VERSION 5.7 ;
BUSBITCHARS "[]" ;
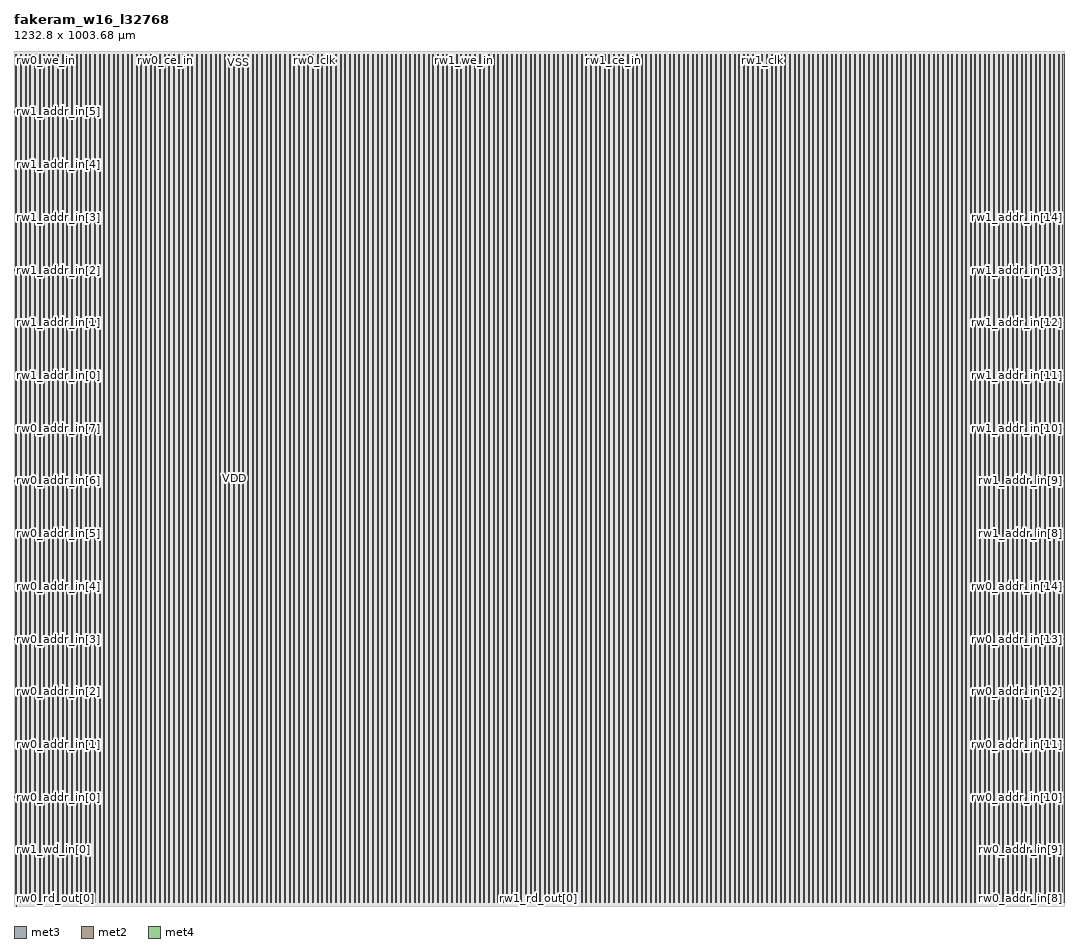
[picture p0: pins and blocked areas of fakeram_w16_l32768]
MACRO fakeram_w16_l32768
  FOREIGN fakeram_w16_l32768 0 0 ;
  SYMMETRY X Y R90 ;
  SIZE 1232.800 BY 1003.680 ;
  CLASS BLOCK ;
  PIN rw0_wd_in[0]
    DIRECTION INPUT ;
    USE SIGNAL ;
    SHAPE ABUTMENT ;
    PORT
      LAYER met3 ;
      RECT 0.000 3.930 0.900 4.230 ;
    END
  END rw0_wd_in[0]
  PIN rw1_wd_in[0]
    DIRECTION INPUT ;
    USE SIGNAL ;
    SHAPE ABUTMENT ;
    PORT
      LAYER met3 ;
      RECT 0.000 65.810 0.900 66.110 ;
    END
  END rw1_wd_in[0]
  PIN rw0_rd_out[0]
    DIRECTION OUTPUT ;
    USE SIGNAL ;
    SHAPE ABUTMENT ;
    PORT
      LAYER met2 ;
      RECT 2.690 0.000 2.830 0.420 ;
    END
  END rw0_rd_out[0]
  PIN rw1_rd_out[0]
    DIRECTION OUTPUT ;
    USE SIGNAL ;
    SHAPE ABUTMENT ;
    PORT
      LAYER met2 ;
      RECT 615.870 0.000 616.010 0.420 ;
    END
  END rw1_rd_out[0]
  PIN rw0_addr_in[0]
    DIRECTION INPUT ;
    USE SIGNAL ;
    SHAPE ABUTMENT ;
    PORT
      LAYER met3 ;
      RECT 0.000 127.690 0.900 127.990 ;
    END
  END rw0_addr_in[0]
  PIN rw0_addr_in[1]
    DIRECTION INPUT ;
    USE SIGNAL ;
    SHAPE ABUTMENT ;
    PORT
      LAYER met3 ;
      RECT 0.000 189.570 0.900 189.870 ;
    END
  END rw0_addr_in[1]
  PIN rw0_addr_in[2]
    DIRECTION INPUT ;
    USE SIGNAL ;
    SHAPE ABUTMENT ;
    PORT
      LAYER met3 ;
      RECT 0.000 251.450 0.900 251.750 ;
    END
  END rw0_addr_in[2]
  PIN rw0_addr_in[3]
    DIRECTION INPUT ;
    USE SIGNAL ;
    SHAPE ABUTMENT ;
    PORT
      LAYER met3 ;
      RECT 0.000 313.330 0.900 313.630 ;
    END
  END rw0_addr_in[3]
  PIN rw0_addr_in[4]
    DIRECTION INPUT ;
    USE SIGNAL ;
    SHAPE ABUTMENT ;
    PORT
      LAYER met3 ;
      RECT 0.000 375.210 0.900 375.510 ;
    END
  END rw0_addr_in[4]
  PIN rw0_addr_in[5]
    DIRECTION INPUT ;
    USE SIGNAL ;
    SHAPE ABUTMENT ;
    PORT
      LAYER met3 ;
      RECT 0.000 437.090 0.900 437.390 ;
    END
  END rw0_addr_in[5]
  PIN rw0_addr_in[6]
    DIRECTION INPUT ;
    USE SIGNAL ;
    SHAPE ABUTMENT ;
    PORT
      LAYER met3 ;
      RECT 0.000 498.970 0.900 499.270 ;
    END
  END rw0_addr_in[6]
  PIN rw0_addr_in[7]
    DIRECTION INPUT ;
    USE SIGNAL ;
    SHAPE ABUTMENT ;
    PORT
      LAYER met3 ;
      RECT 0.000 560.850 0.900 561.150 ;
    END
  END rw0_addr_in[7]
  PIN rw0_addr_in[8]
    DIRECTION INPUT ;
    USE SIGNAL ;
    SHAPE ABUTMENT ;
    PORT
      LAYER met3 ;
      RECT 1231.900 3.930 1232.800 4.230 ;
    END
  END rw0_addr_in[8]
  PIN rw0_addr_in[9]
    DIRECTION INPUT ;
    USE SIGNAL ;
    SHAPE ABUTMENT ;
    PORT
      LAYER met3 ;
      RECT 1231.900 65.810 1232.800 66.110 ;
    END
  END rw0_addr_in[9]
  PIN rw0_addr_in[10]
    DIRECTION INPUT ;
    USE SIGNAL ;
    SHAPE ABUTMENT ;
    PORT
      LAYER met3 ;
      RECT 1231.900 127.690 1232.800 127.990 ;
    END
  END rw0_addr_in[10]
  PIN rw0_addr_in[11]
    DIRECTION INPUT ;
    USE SIGNAL ;
    SHAPE ABUTMENT ;
    PORT
      LAYER met3 ;
      RECT 1231.900 189.570 1232.800 189.870 ;
    END
  END rw0_addr_in[11]
  PIN rw0_addr_in[12]
    DIRECTION INPUT ;
    USE SIGNAL ;
    SHAPE ABUTMENT ;
    PORT
      LAYER met3 ;
      RECT 1231.900 251.450 1232.800 251.750 ;
    END
  END rw0_addr_in[12]
  PIN rw0_addr_in[13]
    DIRECTION INPUT ;
    USE SIGNAL ;
    SHAPE ABUTMENT ;
    PORT
      LAYER met3 ;
      RECT 1231.900 313.330 1232.800 313.630 ;
    END
  END rw0_addr_in[13]
  PIN rw0_addr_in[14]
    DIRECTION INPUT ;
    USE SIGNAL ;
    SHAPE ABUTMENT ;
    PORT
      LAYER met3 ;
      RECT 1231.900 375.210 1232.800 375.510 ;
    END
  END rw0_addr_in[14]
  PIN rw1_addr_in[0]
    DIRECTION INPUT ;
    USE SIGNAL ;
    SHAPE ABUTMENT ;
    PORT
      LAYER met3 ;
      RECT 0.000 622.730 0.900 623.030 ;
    END
  END rw1_addr_in[0]
  PIN rw1_addr_in[1]
    DIRECTION INPUT ;
    USE SIGNAL ;
    SHAPE ABUTMENT ;
    PORT
      LAYER met3 ;
      RECT 0.000 684.610 0.900 684.910 ;
    END
  END rw1_addr_in[1]
  PIN rw1_addr_in[2]
    DIRECTION INPUT ;
    USE SIGNAL ;
    SHAPE ABUTMENT ;
    PORT
      LAYER met3 ;
      RECT 0.000 746.490 0.900 746.790 ;
    END
  END rw1_addr_in[2]
  PIN rw1_addr_in[3]
    DIRECTION INPUT ;
    USE SIGNAL ;
    SHAPE ABUTMENT ;
    PORT
      LAYER met3 ;
      RECT 0.000 808.370 0.900 808.670 ;
    END
  END rw1_addr_in[3]
  PIN rw1_addr_in[4]
    DIRECTION INPUT ;
    USE SIGNAL ;
    SHAPE ABUTMENT ;
    PORT
      LAYER met3 ;
      RECT 0.000 870.250 0.900 870.550 ;
    END
  END rw1_addr_in[4]
  PIN rw1_addr_in[5]
    DIRECTION INPUT ;
    USE SIGNAL ;
    SHAPE ABUTMENT ;
    PORT
      LAYER met3 ;
      RECT 0.000 932.130 0.900 932.430 ;
    END
  END rw1_addr_in[5]
  PIN rw1_addr_in[6]
    DIRECTION INPUT ;
    USE SIGNAL ;
    SHAPE ABUTMENT ;
    PORT
      LAYER met3 ;
      RECT 0.000 994.010 0.900 994.310 ;
    END
  END rw1_addr_in[6]
  PIN rw1_addr_in[7]
    DIRECTION INPUT ;
    USE SIGNAL ;
    SHAPE ABUTMENT ;
    PORT
      LAYER met3 ;
      RECT 0.000 1055.890 0.900 1056.190 ;
    END
  END rw1_addr_in[7]
  PIN rw1_addr_in[8]
    DIRECTION INPUT ;
    USE SIGNAL ;
    SHAPE ABUTMENT ;
    PORT
      LAYER met3 ;
      RECT 1231.900 437.090 1232.800 437.390 ;
    END
  END rw1_addr_in[8]
  PIN rw1_addr_in[9]
    DIRECTION INPUT ;
    USE SIGNAL ;
    SHAPE ABUTMENT ;
    PORT
      LAYER met3 ;
      RECT 1231.900 498.970 1232.800 499.270 ;
    END
  END rw1_addr_in[9]
  PIN rw1_addr_in[10]
    DIRECTION INPUT ;
    USE SIGNAL ;
    SHAPE ABUTMENT ;
    PORT
      LAYER met3 ;
      RECT 1231.900 560.850 1232.800 561.150 ;
    END
  END rw1_addr_in[10]
  PIN rw1_addr_in[11]
    DIRECTION INPUT ;
    USE SIGNAL ;
    SHAPE ABUTMENT ;
    PORT
      LAYER met3 ;
      RECT 1231.900 622.730 1232.800 623.030 ;
    END
  END rw1_addr_in[11]
  PIN rw1_addr_in[12]
    DIRECTION INPUT ;
    USE SIGNAL ;
    SHAPE ABUTMENT ;
    PORT
      LAYER met3 ;
      RECT 1231.900 684.610 1232.800 684.910 ;
    END
  END rw1_addr_in[12]
  PIN rw1_addr_in[13]
    DIRECTION INPUT ;
    USE SIGNAL ;
    SHAPE ABUTMENT ;
    PORT
      LAYER met3 ;
      RECT 1231.900 746.490 1232.800 746.790 ;
    END
  END rw1_addr_in[13]
  PIN rw1_addr_in[14]
    DIRECTION INPUT ;
    USE SIGNAL ;
    SHAPE ABUTMENT ;
    PORT
      LAYER met3 ;
      RECT 1231.900 808.370 1232.800 808.670 ;
    END
  END rw1_addr_in[14]
  PIN rw0_we_in
    DIRECTION INPUT ;
    USE SIGNAL ;
    SHAPE ABUTMENT ;
    PORT
      LAYER met2 ;
      RECT 2.690 1003.260 2.830 1003.680 ;
    END
  END rw0_we_in
  PIN rw0_ce_in
    DIRECTION INPUT ;
    USE SIGNAL ;
    SHAPE ABUTMENT ;
    PORT
      LAYER met2 ;
      RECT 177.950 1003.260 178.090 1003.680 ;
    END
  END rw0_ce_in
  PIN rw0_clk
    DIRECTION INPUT ;
    USE SIGNAL ;
    SHAPE ABUTMENT ;
    PORT
      LAYER met2 ;
      RECT 353.210 1003.260 353.350 1003.680 ;
    END
  END rw0_clk
  PIN rw1_we_in
    DIRECTION INPUT ;
    USE SIGNAL ;
    SHAPE ABUTMENT ;
    PORT
      LAYER met2 ;
      RECT 528.470 1003.260 528.610 1003.680 ;
    END
  END rw1_we_in
  PIN rw1_ce_in
    DIRECTION INPUT ;
    USE SIGNAL ;
    SHAPE ABUTMENT ;
    PORT
      LAYER met2 ;
      RECT 703.730 1003.260 703.870 1003.680 ;
    END
  END rw1_ce_in
  PIN rw1_clk
    DIRECTION INPUT ;
    USE SIGNAL ;
    SHAPE ABUTMENT ;
    PORT
      LAYER met2 ;
      RECT 878.990 1003.260 879.130 1003.680 ;
    END
  END rw1_clk
  PIN VSS
    DIRECTION INOUT ;
    USE GROUND ;
    PORT
      LAYER met4 ;
      RECT 2.160 4.080 3.360 999.600 ;
      RECT 13.040 4.080 14.240 999.600 ;
      RECT 23.920 4.080 25.120 999.600 ;
      RECT 34.800 4.080 36.000 999.600 ;
      RECT 45.680 4.080 46.880 999.600 ;
      RECT 56.560 4.080 57.760 999.600 ;
      RECT 67.440 4.080 68.640 999.600 ;
      RECT 78.320 4.080 79.520 999.600 ;
      RECT 89.200 4.080 90.400 999.600 ;
      RECT 100.080 4.080 101.280 999.600 ;
      RECT 110.960 4.080 112.160 999.600 ;
      RECT 121.840 4.080 123.040 999.600 ;
      RECT 132.720 4.080 133.920 999.600 ;
      RECT 143.600 4.080 144.800 999.600 ;
      RECT 154.480 4.080 155.680 999.600 ;
      RECT 165.360 4.080 166.560 999.600 ;
      RECT 176.240 4.080 177.440 999.600 ;
      RECT 187.120 4.080 188.320 999.600 ;
      RECT 198.000 4.080 199.200 999.600 ;
      RECT 208.880 4.080 210.080 999.600 ;
      RECT 219.760 4.080 220.960 999.600 ;
      RECT 230.640 4.080 231.840 999.600 ;
      RECT 241.520 4.080 242.720 999.600 ;
      RECT 252.400 4.080 253.600 999.600 ;
      RECT 263.280 4.080 264.480 999.600 ;
      RECT 274.160 4.080 275.360 999.600 ;
      RECT 285.040 4.080 286.240 999.600 ;
      RECT 295.920 4.080 297.120 999.600 ;
      RECT 306.800 4.080 308.000 999.600 ;
      RECT 317.680 4.080 318.880 999.600 ;
      RECT 328.560 4.080 329.760 999.600 ;
      RECT 339.440 4.080 340.640 999.600 ;
      RECT 350.320 4.080 351.520 999.600 ;
      RECT 361.200 4.080 362.400 999.600 ;
      RECT 372.080 4.080 373.280 999.600 ;
      RECT 382.960 4.080 384.160 999.600 ;
      RECT 393.840 4.080 395.040 999.600 ;
      RECT 404.720 4.080 405.920 999.600 ;
      RECT 415.600 4.080 416.800 999.600 ;
      RECT 426.480 4.080 427.680 999.600 ;
      RECT 437.360 4.080 438.560 999.600 ;
      RECT 448.240 4.080 449.440 999.600 ;
      RECT 459.120 4.080 460.320 999.600 ;
      RECT 470.000 4.080 471.200 999.600 ;
      RECT 480.880 4.080 482.080 999.600 ;
      RECT 491.760 4.080 492.960 999.600 ;
      RECT 502.640 4.080 503.840 999.600 ;
      RECT 513.520 4.080 514.720 999.600 ;
      RECT 524.400 4.080 525.600 999.600 ;
      RECT 535.280 4.080 536.480 999.600 ;
      RECT 546.160 4.080 547.360 999.600 ;
      RECT 557.040 4.080 558.240 999.600 ;
      RECT 567.920 4.080 569.120 999.600 ;
      RECT 578.800 4.080 580.000 999.600 ;
      RECT 589.680 4.080 590.880 999.600 ;
      RECT 600.560 4.080 601.760 999.600 ;
      RECT 611.440 4.080 612.640 999.600 ;
      RECT 622.320 4.080 623.520 999.600 ;
      RECT 633.200 4.080 634.400 999.600 ;
      RECT 644.080 4.080 645.280 999.600 ;
      RECT 654.960 4.080 656.160 999.600 ;
      RECT 665.840 4.080 667.040 999.600 ;
      RECT 676.720 4.080 677.920 999.600 ;
      RECT 687.600 4.080 688.800 999.600 ;
      RECT 698.480 4.080 699.680 999.600 ;
      RECT 709.360 4.080 710.560 999.600 ;
      RECT 720.240 4.080 721.440 999.600 ;
      RECT 731.120 4.080 732.320 999.600 ;
      RECT 742.000 4.080 743.200 999.600 ;
      RECT 752.880 4.080 754.080 999.600 ;
      RECT 763.760 4.080 764.960 999.600 ;
      RECT 774.640 4.080 775.840 999.600 ;
      RECT 785.520 4.080 786.720 999.600 ;
      RECT 796.400 4.080 797.600 999.600 ;
      RECT 807.280 4.080 808.480 999.600 ;
      RECT 818.160 4.080 819.360 999.600 ;
      RECT 829.040 4.080 830.240 999.600 ;
      RECT 839.920 4.080 841.120 999.600 ;
      RECT 850.800 4.080 852.000 999.600 ;
      RECT 861.680 4.080 862.880 999.600 ;
      RECT 872.560 4.080 873.760 999.600 ;
      RECT 883.440 4.080 884.640 999.600 ;
      RECT 894.320 4.080 895.520 999.600 ;
      RECT 905.200 4.080 906.400 999.600 ;
      RECT 916.080 4.080 917.280 999.600 ;
      RECT 926.960 4.080 928.160 999.600 ;
      RECT 937.840 4.080 939.040 999.600 ;
      RECT 948.720 4.080 949.920 999.600 ;
      RECT 959.600 4.080 960.800 999.600 ;
      RECT 970.480 4.080 971.680 999.600 ;
      RECT 981.360 4.080 982.560 999.600 ;
      RECT 992.240 4.080 993.440 999.600 ;
      RECT 1003.120 4.080 1004.320 999.600 ;
      RECT 1014.000 4.080 1015.200 999.600 ;
      RECT 1024.880 4.080 1026.080 999.600 ;
      RECT 1035.760 4.080 1036.960 999.600 ;
      RECT 1046.640 4.080 1047.840 999.600 ;
      RECT 1057.520 4.080 1058.720 999.600 ;
      RECT 1068.400 4.080 1069.600 999.600 ;
      RECT 1079.280 4.080 1080.480 999.600 ;
      RECT 1090.160 4.080 1091.360 999.600 ;
      RECT 1101.040 4.080 1102.240 999.600 ;
      RECT 1111.920 4.080 1113.120 999.600 ;
      RECT 1122.800 4.080 1124.000 999.600 ;
      RECT 1133.680 4.080 1134.880 999.600 ;
      RECT 1144.560 4.080 1145.760 999.600 ;
      RECT 1155.440 4.080 1156.640 999.600 ;
      RECT 1166.320 4.080 1167.520 999.600 ;
      RECT 1177.200 4.080 1178.400 999.600 ;
      RECT 1188.080 4.080 1189.280 999.600 ;
      RECT 1198.960 4.080 1200.160 999.600 ;
      RECT 1209.840 4.080 1211.040 999.600 ;
      RECT 1220.720 4.080 1221.920 999.600 ;
      RECT 1231.600 4.080 1232.800 999.600 ;
    END
  END VSS
  PIN VDD
    DIRECTION INOUT ;
    USE POWER ;
    PORT
      LAYER met4 ;
      RECT 7.600 4.080 8.800 999.600 ;
      RECT 18.480 4.080 19.680 999.600 ;
      RECT 29.360 4.080 30.560 999.600 ;
      RECT 40.240 4.080 41.440 999.600 ;
      RECT 51.120 4.080 52.320 999.600 ;
      RECT 62.000 4.080 63.200 999.600 ;
      RECT 72.880 4.080 74.080 999.600 ;
      RECT 83.760 4.080 84.960 999.600 ;
      RECT 94.640 4.080 95.840 999.600 ;
      RECT 105.520 4.080 106.720 999.600 ;
      RECT 116.400 4.080 117.600 999.600 ;
      RECT 127.280 4.080 128.480 999.600 ;
      RECT 138.160 4.080 139.360 999.600 ;
      RECT 149.040 4.080 150.240 999.600 ;
      RECT 159.920 4.080 161.120 999.600 ;
      RECT 170.800 4.080 172.000 999.600 ;
      RECT 181.680 4.080 182.880 999.600 ;
      RECT 192.560 4.080 193.760 999.600 ;
      RECT 203.440 4.080 204.640 999.600 ;
      RECT 214.320 4.080 215.520 999.600 ;
      RECT 225.200 4.080 226.400 999.600 ;
      RECT 236.080 4.080 237.280 999.600 ;
      RECT 246.960 4.080 248.160 999.600 ;
      RECT 257.840 4.080 259.040 999.600 ;
      RECT 268.720 4.080 269.920 999.600 ;
      RECT 279.600 4.080 280.800 999.600 ;
      RECT 290.480 4.080 291.680 999.600 ;
      RECT 301.360 4.080 302.560 999.600 ;
      RECT 312.240 4.080 313.440 999.600 ;
      RECT 323.120 4.080 324.320 999.600 ;
      RECT 334.000 4.080 335.200 999.600 ;
      RECT 344.880 4.080 346.080 999.600 ;
      RECT 355.760 4.080 356.960 999.600 ;
      RECT 366.640 4.080 367.840 999.600 ;
      RECT 377.520 4.080 378.720 999.600 ;
      RECT 388.400 4.080 389.600 999.600 ;
      RECT 399.280 4.080 400.480 999.600 ;
      RECT 410.160 4.080 411.360 999.600 ;
      RECT 421.040 4.080 422.240 999.600 ;
      RECT 431.920 4.080 433.120 999.600 ;
      RECT 442.800 4.080 444.000 999.600 ;
      RECT 453.680 4.080 454.880 999.600 ;
      RECT 464.560 4.080 465.760 999.600 ;
      RECT 475.440 4.080 476.640 999.600 ;
      RECT 486.320 4.080 487.520 999.600 ;
      RECT 497.200 4.080 498.400 999.600 ;
      RECT 508.080 4.080 509.280 999.600 ;
      RECT 518.960 4.080 520.160 999.600 ;
      RECT 529.840 4.080 531.040 999.600 ;
      RECT 540.720 4.080 541.920 999.600 ;
      RECT 551.600 4.080 552.800 999.600 ;
      RECT 562.480 4.080 563.680 999.600 ;
      RECT 573.360 4.080 574.560 999.600 ;
      RECT 584.240 4.080 585.440 999.600 ;
      RECT 595.120 4.080 596.320 999.600 ;
      RECT 606.000 4.080 607.200 999.600 ;
      RECT 616.880 4.080 618.080 999.600 ;
      RECT 627.760 4.080 628.960 999.600 ;
      RECT 638.640 4.080 639.840 999.600 ;
      RECT 649.520 4.080 650.720 999.600 ;
      RECT 660.400 4.080 661.600 999.600 ;
      RECT 671.280 4.080 672.480 999.600 ;
      RECT 682.160 4.080 683.360 999.600 ;
      RECT 693.040 4.080 694.240 999.600 ;
      RECT 703.920 4.080 705.120 999.600 ;
      RECT 714.800 4.080 716.000 999.600 ;
      RECT 725.680 4.080 726.880 999.600 ;
      RECT 736.560 4.080 737.760 999.600 ;
      RECT 747.440 4.080 748.640 999.600 ;
      RECT 758.320 4.080 759.520 999.600 ;
      RECT 769.200 4.080 770.400 999.600 ;
      RECT 780.080 4.080 781.280 999.600 ;
      RECT 790.960 4.080 792.160 999.600 ;
      RECT 801.840 4.080 803.040 999.600 ;
      RECT 812.720 4.080 813.920 999.600 ;
      RECT 823.600 4.080 824.800 999.600 ;
      RECT 834.480 4.080 835.680 999.600 ;
      RECT 845.360 4.080 846.560 999.600 ;
      RECT 856.240 4.080 857.440 999.600 ;
      RECT 867.120 4.080 868.320 999.600 ;
      RECT 878.000 4.080 879.200 999.600 ;
      RECT 888.880 4.080 890.080 999.600 ;
      RECT 899.760 4.080 900.960 999.600 ;
      RECT 910.640 4.080 911.840 999.600 ;
      RECT 921.520 4.080 922.720 999.600 ;
      RECT 932.400 4.080 933.600 999.600 ;
      RECT 943.280 4.080 944.480 999.600 ;
      RECT 954.160 4.080 955.360 999.600 ;
      RECT 965.040 4.080 966.240 999.600 ;
      RECT 975.920 4.080 977.120 999.600 ;
      RECT 986.800 4.080 988.000 999.600 ;
      RECT 997.680 4.080 998.880 999.600 ;
      RECT 1008.560 4.080 1009.760 999.600 ;
      RECT 1019.440 4.080 1020.640 999.600 ;
      RECT 1030.320 4.080 1031.520 999.600 ;
      RECT 1041.200 4.080 1042.400 999.600 ;
      RECT 1052.080 4.080 1053.280 999.600 ;
      RECT 1062.960 4.080 1064.160 999.600 ;
      RECT 1073.840 4.080 1075.040 999.600 ;
      RECT 1084.720 4.080 1085.920 999.600 ;
      RECT 1095.600 4.080 1096.800 999.600 ;
      RECT 1106.480 4.080 1107.680 999.600 ;
      RECT 1117.360 4.080 1118.560 999.600 ;
      RECT 1128.240 4.080 1129.440 999.600 ;
      RECT 1139.120 4.080 1140.320 999.600 ;
      RECT 1150.000 4.080 1151.200 999.600 ;
      RECT 1160.880 4.080 1162.080 999.600 ;
      RECT 1171.760 4.080 1172.960 999.600 ;
      RECT 1182.640 4.080 1183.840 999.600 ;
      RECT 1193.520 4.080 1194.720 999.600 ;
      RECT 1204.400 4.080 1205.600 999.600 ;
      RECT 1215.280 4.080 1216.480 999.600 ;
      RECT 1226.160 4.080 1227.360 999.600 ;
    END
  END VDD
  OBS
    LAYER met1 ;
    RECT 0 0 1232.800 1003.680 ;
    LAYER met2 ;
    RECT 0 0 1232.800 1003.680 ;
    LAYER met3 ;
    RECT 0 0 1232.800 1003.680 ;
    LAYER met4 ;
    RECT 0 0 1232.800 1003.680 ;
  END
END fakeram_w16_l32768

END LIBRARY
